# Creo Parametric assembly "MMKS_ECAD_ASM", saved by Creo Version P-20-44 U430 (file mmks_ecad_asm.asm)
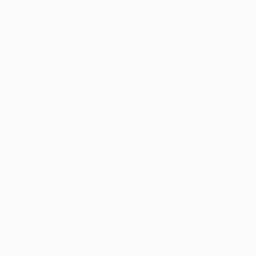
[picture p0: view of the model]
Units: millimeter Kilogram Sec (mmKs); MM, KILOGRAM, SECS

Created from: ASM0001.ASM

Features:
  1. datum plane "ADTM1", "ASM_RIGHT"
  2. datum plane "ADTM2", "ASM_TOP"
  3. datum plane "ADTM3", "ASM_FRONT"
  4. coordinate system "ACS0"

Other named items: ECAD_DEFAULT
